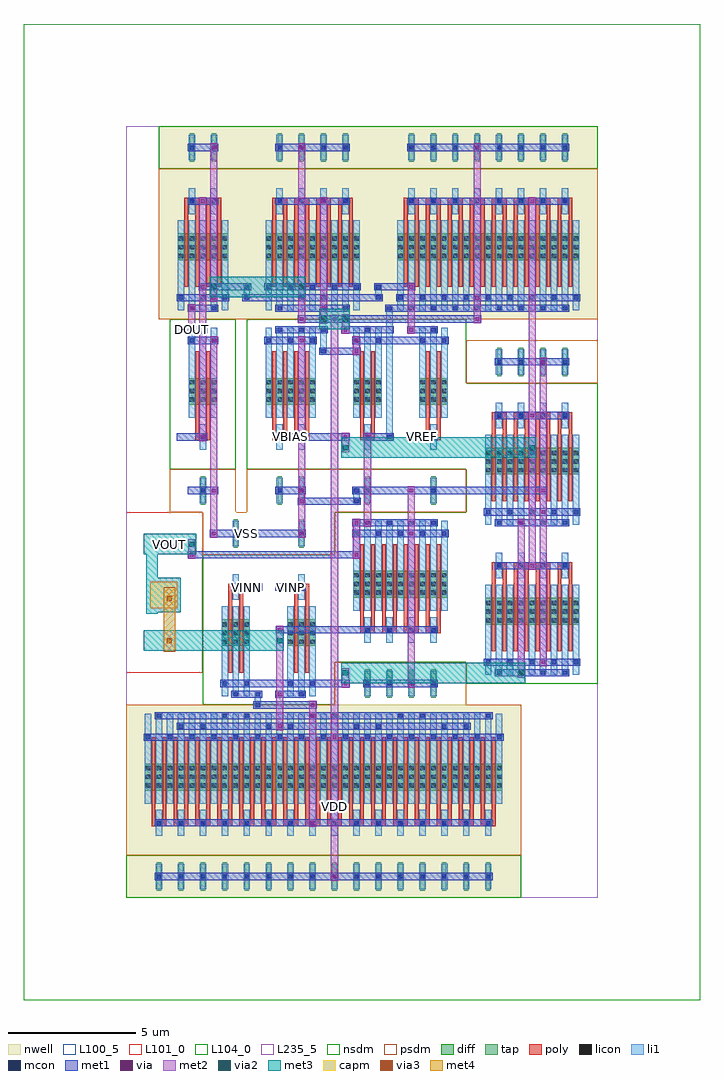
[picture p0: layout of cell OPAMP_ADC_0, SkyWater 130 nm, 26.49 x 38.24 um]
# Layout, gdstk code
from math import pi, radians
import gdstk
lib = gdstk.Library(unit=1e-6, precision=1e-09)
def R(c, l, rs):  # rectangles x0, y0, x1, y1
    for r in rs: c.add(gdstk.rectangle(r[:2], r[2:], *l))
def A(c, l, x, y, w, h, nx, ny, dx, dy):  # array of equal rectangles
    R(c, l, [(x+i*dx, y+j*dy, x+i*dx+w, y+j*dy+h) for i in range(nx) for j in range(ny)])
def P(c, l, *ps):  # polygons
    for p in ps: c.add(gdstk.Polygon(p, *l))
nwell = (64, 20)
diff = (65, 20)
tap = (65, 44)
poly = (66, 20)
licon = (66, 44)
li1 = (67, 20)
mcon = (67, 44)
met1 = (68, 20)
via = (68, 44)
met2 = (69, 20)
via2 = (69, 44)
met3 = (70, 20)
via3 = (70, 44)
met4 = (71, 20)
capm = (89, 44)
nsdm = (93, 44)
psdm = (94, 20)
L100_5 = (100, 5)
L101_0 = (101, 0)
L104_0 = (104, 0)
L235_5 = (235, 5)

scm_pmos_2270758_x8_y1_1 = lib.new_cell('SCM_PMOS_2270758_X8_Y1_1785374631')
R(scm_pmos_2270758_x8_y1_1, nwell, [(0,0,15.48,7.56)])
R(scm_pmos_2270758_x8_y1_1, diff, [(0.735,2.31,14.745,3.36)])
A(scm_pmos_2270758_x8_y1_1, tap, 1.205, 6.16, 0.17, 1.12, 16, 1, 0.86, 0)
A(scm_pmos_2270758_x8_y1_1, poly, 1, 1.26, 0.15, 3.36, 32, 1, 0.43, 0)
A(scm_pmos_2270758_x8_y1_1, poly, 1, 4.485, 0.58, 0.27, 16, 1, 0.86, 0)
A(scm_pmos_2270758_x8_y1_1, licon, 0.775, 2.39, 0.17, 0.17, 3, 3, 0.43, 0.34)
A(scm_pmos_2270758_x8_y1_1, licon, 1.635, 2.39, 0.17, 0.17, 3, 3, 0.43, 0.34)
A(scm_pmos_2270758_x8_y1_1, licon, 2.495, 2.39, 0.17, 0.17, 3, 3, 0.43, 0.34)
A(scm_pmos_2270758_x8_y1_1, licon, 3.355, 2.39, 0.17, 0.17, 3, 3, 0.43, 0.34)
A(scm_pmos_2270758_x8_y1_1, licon, 4.215, 2.39, 0.17, 0.17, 3, 3, 0.43, 0.34)
A(scm_pmos_2270758_x8_y1_1, licon, 5.075, 2.39, 0.17, 0.17, 3, 3, 0.43, 0.34)
A(scm_pmos_2270758_x8_y1_1, licon, 5.935, 2.39, 0.17, 0.17, 3, 3, 0.43, 0.34)
A(scm_pmos_2270758_x8_y1_1, licon, 6.795, 2.39, 0.17, 0.17, 3, 3, 0.43, 0.34)
A(scm_pmos_2270758_x8_y1_1, licon, 7.655, 2.39, 0.17, 0.17, 3, 3, 0.43, 0.34)
A(scm_pmos_2270758_x8_y1_1, licon, 8.515, 2.39, 0.17, 0.17, 3, 3, 0.43, 0.34)
A(scm_pmos_2270758_x8_y1_1, licon, 9.375, 2.39, 0.17, 0.17, 3, 3, 0.43, 0.34)
A(scm_pmos_2270758_x8_y1_1, licon, 10.235, 2.39, 0.17, 0.17, 3, 3, 0.43, 0.34)
A(scm_pmos_2270758_x8_y1_1, licon, 11.095, 2.39, 0.17, 0.17, 3, 3, 0.43, 0.34)
A(scm_pmos_2270758_x8_y1_1, licon, 11.955, 2.39, 0.17, 0.17, 3, 3, 0.43, 0.34)
A(scm_pmos_2270758_x8_y1_1, licon, 12.815, 2.39, 0.17, 0.17, 3, 3, 0.43, 0.34)
A(scm_pmos_2270758_x8_y1_1, licon, 13.675, 2.39, 0.17, 0.17, 3, 3, 0.43, 0.34)
A(scm_pmos_2270758_x8_y1_1, licon, 1.205, 4.535, 0.17, 0.17, 16, 2, 0.86, 2.1)
A(scm_pmos_2270758_x8_y1_1, li1, 0.735, 0.335, 0.25, 3.53, 33, 1, 0.43, 0)
A(scm_pmos_2270758_x8_y1_1, li1, 1.165, 4.115, 0.25, 1.01, 16, 2, 0.86, 2.1)
A(scm_pmos_2270758_x8_y1_1, mcon, 0.775, 1.175, 0.17, 0.17, 17, 1, 0.86, 0)
A(scm_pmos_2270758_x8_y1_1, mcon, 1.205, 4.535, 0.17, 0.17, 16, 2, 0.86, 2.1)
R(scm_pmos_2270758_x8_y1_1, mcon, [(1.205,0.335,1.375,0.505), (3.785,0.335,3.955,0.505), (4.645,0.335,4.815,0.505), (7.225,0.335,7.395,0.505), (8.085,0.335,8.255,0.505), (10.665,0.335,10.835,0.505), (11.525,0.335,11.695,0.505), (14.105,0.335,14.275,0.505), (2.065,0.755,2.235,0.925), (2.925,0.755,3.095,0.925), (5.505,0.755,5.675,0.925), (6.365,0.755,6.535,0.925), (8.945,0.755,9.115,0.925), (9.805,0.755,9.975,0.925), (12.385,0.755,12.555,0.925), (13.245,0.755,13.415,0.925)])
R(scm_pmos_2270758_x8_y1_1, met1, [(1.12,0.28,14.36,0.56), (1.98,0.7,13.5,0.98), (0.69,1.12,14.79,1.4), (1.12,4.48,14.36,4.76), (1.12,6.58,14.36,6.86)])
R(scm_pmos_2270758_x8_y1_1, via, [(7.235,0.345,7.385,0.495), (8.095,1.185,8.245,1.335), (7.235,4.545,7.385,4.695), (8.095,6.645,8.245,6.795)])
R(scm_pmos_2270758_x8_y1_1, met2, [(7.17,0.26,7.45,4.78), (8.03,1.1,8.31,6.88)])
R(scm_pmos_2270758_x8_y1_1, nsdm, [(0,5.88,15.48,7.56)])
R(scm_pmos_2270758_x8_y1_1, psdm, [(0,0,15.48,5.88)])
R(scm_pmos_2270758_x8_y1_1, L100_5, [(0,0,15.48,7.56)])

scm_pmos_89224135_x2_y1_ = lib.new_cell('SCM_PMOS_89224135_X2_Y1_1785374632')
R(scm_pmos_89224135_x2_y1_, nwell, [(0,0,5.16,7.56)])
R(scm_pmos_89224135_x2_y1_, diff, [(0.735,2.31,4.425,3.36)])
A(scm_pmos_89224135_x2_y1_, tap, 1.205, 6.16, 0.17, 1.12, 4, 1, 0.86, 0)
A(scm_pmos_89224135_x2_y1_, poly, 1, 1.26, 0.15, 3.36, 8, 1, 0.43, 0)
A(scm_pmos_89224135_x2_y1_, poly, 1, 4.485, 0.58, 0.27, 4, 1, 0.86, 0)
A(scm_pmos_89224135_x2_y1_, licon, 0.775, 2.39, 0.17, 0.17, 3, 3, 0.43, 0.34)
A(scm_pmos_89224135_x2_y1_, licon, 1.635, 2.39, 0.17, 0.17, 3, 3, 0.43, 0.34)
A(scm_pmos_89224135_x2_y1_, licon, 2.495, 2.39, 0.17, 0.17, 3, 3, 0.43, 0.34)
A(scm_pmos_89224135_x2_y1_, licon, 3.355, 2.39, 0.17, 0.17, 3, 3, 0.43, 0.34)
A(scm_pmos_89224135_x2_y1_, licon, 1.205, 4.535, 0.17, 0.17, 4, 2, 0.86, 2.1)
A(scm_pmos_89224135_x2_y1_, li1, 0.735, 0.335, 0.25, 3.53, 9, 1, 0.43, 0)
A(scm_pmos_89224135_x2_y1_, li1, 1.165, 4.115, 0.25, 1.01, 4, 2, 0.86, 2.1)
A(scm_pmos_89224135_x2_y1_, mcon, 0.775, 1.175, 0.17, 0.17, 5, 1, 0.86, 0)
A(scm_pmos_89224135_x2_y1_, mcon, 1.205, 4.535, 0.17, 0.17, 4, 2, 0.86, 2.1)
R(scm_pmos_89224135_x2_y1_, mcon, [(1.205,0.335,1.375,0.505), (3.785,0.335,3.955,0.505), (2.065,0.755,2.235,0.925), (2.925,0.755,3.095,0.925)])
R(scm_pmos_89224135_x2_y1_, met1, [(1.12,0.28,4.04,0.56), (1.98,0.7,3.18,0.98), (0.69,1.12,4.47,1.4), (1.12,4.48,4.04,4.76), (1.12,6.58,4.04,6.86)])
R(scm_pmos_89224135_x2_y1_, via, [(2.075,0.345,2.225,0.495), (2.935,1.185,3.085,1.335), (2.075,4.545,2.225,4.695), (2.935,6.645,3.085,6.795)])
R(scm_pmos_89224135_x2_y1_, met2, [(2.01,0.26,2.29,4.78), (2.87,1.1,3.15,6.88)])
R(scm_pmos_89224135_x2_y1_, nsdm, [(0,5.88,5.16,7.56)])
R(scm_pmos_89224135_x2_y1_, psdm, [(0,0,5.16,5.88)])
R(scm_pmos_89224135_x2_y1_, L100_5, [(0,0,5.16,7.56)])

nmos_s_66450264_x1_y1_17 = lib.new_cell('NMOS_S_66450264_X1_Y1_1785374624_1785374624')
R(nmos_s_66450264_x1_y1_17, diff, [(0.735,2.31,1.845,3.36)])
R(nmos_s_66450264_x1_y1_17, tap, [(1.205,6.16,1.375,7.28)])
R(nmos_s_66450264_x1_y1_17, poly, [(1,1.26,1.15,4.62), (1.43,1.26,1.58,4.62), (1,4.485,1.58,4.755)])
A(nmos_s_66450264_x1_y1_17, licon, 0.775, 2.39, 0.17, 0.17, 3, 3, 0.43, 0.34)
R(nmos_s_66450264_x1_y1_17, licon, [(1.205,4.535,1.375,4.705), (1.205,6.635,1.375,6.805)])
A(nmos_s_66450264_x1_y1_17, li1, 0.735, 0.335, 0.25, 3.53, 3, 1, 0.43, 0)
R(nmos_s_66450264_x1_y1_17, li1, [(1.165,4.115,1.415,5.125), (1.165,6.215,1.415,7.225)])
R(nmos_s_66450264_x1_y1_17, mcon, [(1.205,0.335,1.375,0.505), (0.775,0.755,0.945,0.925), (1.635,0.755,1.805,0.925), (1.205,4.535,1.375,4.705), (1.205,6.635,1.375,6.805)])
R(nmos_s_66450264_x1_y1_17, met1, [(0.26,0.28,1.46,0.56), (0.69,0.7,1.89,0.98), (0.26,4.48,1.46,4.76), (0.69,6.58,1.89,6.86)])
R(nmos_s_66450264_x1_y1_17, via, [(1.645,0.765,1.795,0.915), (1.645,6.645,1.795,6.795)])
R(nmos_s_66450264_x1_y1_17, met2, [(1.58,0.68,1.86,6.88)])
R(nmos_s_66450264_x1_y1_17, nsdm, [(0,0,2.58,5.88)])
R(nmos_s_66450264_x1_y1_17, psdm, [(0,5.88,2.58,7.56)])
R(nmos_s_66450264_x1_y1_17, L100_5, [(0,0,2.58,7.56)])

pmos_s_5293867_x2_y1_178 = lib.new_cell('PMOS_S_5293867_X2_Y1_1785374625_1785374624')
R(pmos_s_5293867_x2_y1_178, nwell, [(0,0,3.44,7.56)])
R(pmos_s_5293867_x2_y1_178, diff, [(0.735,2.31,2.705,3.36)])
R(pmos_s_5293867_x2_y1_178, tap, [(1.205,6.16,1.375,7.28), (2.065,6.16,2.235,7.28)])
A(pmos_s_5293867_x2_y1_178, poly, 1, 1.26, 0.15, 3.36, 4, 1, 0.43, 0)
R(pmos_s_5293867_x2_y1_178, poly, [(1,4.485,1.58,4.755), (1.86,4.485,2.44,4.755)])
A(pmos_s_5293867_x2_y1_178, licon, 0.775, 2.39, 0.17, 0.17, 3, 3, 0.43, 0.34)
A(pmos_s_5293867_x2_y1_178, licon, 1.635, 2.39, 0.17, 0.17, 3, 3, 0.43, 0.34)
R(pmos_s_5293867_x2_y1_178, licon, [(1.205,4.535,1.375,4.705), (2.065,4.535,2.235,4.705), (1.205,6.635,1.375,6.805), (2.065,6.635,2.235,6.805)])
A(pmos_s_5293867_x2_y1_178, li1, 0.735, 0.335, 0.25, 3.53, 5, 1, 0.43, 0)
R(pmos_s_5293867_x2_y1_178, li1, [(1.165,4.115,1.415,5.125), (2.025,4.115,2.275,5.125), (1.165,6.215,1.415,7.225), (2.025,6.215,2.275,7.225)])
A(pmos_s_5293867_x2_y1_178, mcon, 0.775, 0.755, 0.17, 0.17, 3, 1, 0.86, 0)
R(pmos_s_5293867_x2_y1_178, mcon, [(1.205,0.335,1.375,0.505), (2.065,0.335,2.235,0.505), (1.205,4.535,1.375,4.705), (2.065,4.535,2.235,4.705), (1.205,6.635,1.375,6.805), (2.065,6.635,2.235,6.805)])
R(pmos_s_5293867_x2_y1_178, met1, [(1.12,0.28,2.32,0.56), (0.69,0.7,2.75,0.98), (1.12,4.48,2.32,4.76), (1.12,6.58,2.32,6.86)])
R(pmos_s_5293867_x2_y1_178, via, [(2.075,0.765,2.225,0.915), (2.075,6.645,2.225,6.795)])
R(pmos_s_5293867_x2_y1_178, met2, [(2.01,0.68,2.29,6.88)])
R(pmos_s_5293867_x2_y1_178, nsdm, [(0,5.88,3.44,7.56)])
R(pmos_s_5293867_x2_y1_178, psdm, [(0,0,3.44,5.88)])
R(pmos_s_5293867_x2_y1_178, L100_5, [(0,0,3.44,7.56)])

inv_65002554_0_178537462 = lib.new_cell('INV_65002554_0_1785374624')
R(inv_65002554_0_178537462, met1, [(1.56,2.8,1.88,3.08), (1.56,2.8,1.88,3.08), (1.13,7,1.45,7.28), (1.13,7,1.45,7.28), (1.13,7.84,1.45,8.12), (1.13,7.84,1.45,8.12), (1.56,12.04,1.88,12.32), (1.56,12.04,1.88,12.32)])
P(inv_65002554_0_178537462, met1, [(0,0),(0,0),(0,0),(0,0)],
  [(0,0),(0,0),(0,0),(0,0)],
  [(0,0),(0,0),(0,0),(0,0)],
  [(0,0),(0,0),(0,0),(0,0)])
R(inv_65002554_0_178537462, via, [(1.645,2.865,1.795,3.015), (1.645,2.865,1.795,3.015), (1.215,7.065,1.365,7.215), (1.215,7.065,1.365,7.215), (1.215,7.905,1.365,8.055), (1.215,7.905,1.365,8.055), (1.645,12.105,1.795,12.255), (1.645,12.105,1.795,12.255)])
R(inv_65002554_0_178537462, met2, [(1.58,2.78,1.86,3.1), (1.58,2.78,1.86,3.1), (1.58,2.94,1.86,12.18), (1.15,6.98,1.43,7.3), (1.15,6.98,1.43,7.3), (1.15,7.14,1.43,7.98), (1.15,7.82,1.43,8.14), (1.15,7.82,1.43,8.14), (1.58,12.02,1.86,12.34), (1.58,12.02,1.86,12.34)])
P(inv_65002554_0_178537462, met2, [(0,0),(0,0),(0,0),(0,0)],
  [(0,0),(0,0),(0,0),(0,0)])
R(inv_65002554_0_178537462, L235_5, [(0,0,3.44,15.12)])
inv_65002554_0_178537462.add(gdstk.Reference(nmos_s_66450264_x1_y1_17, (0.43,7.56), x_reflection=True))
inv_65002554_0_178537462.add(gdstk.Reference(pmos_s_5293867_x2_y1_178, (0,7.56)))

cap_2t_96113034_17853746 = lib.new_cell('CAP_2T_96113034_1785374625')
R(cap_2t_96113034_17853746, met3, [(0.265,0.86,2.315,1.66), (1.76,2.32,2.21,4.84), (0.86,2.37,2.21,3.72), (0.265,4.64,2.315,5.44)])
R(cap_2t_96113034_17853746, via3, [(1.21,1.16,1.41,1.36), (1.21,2.82,1.41,3.02)])
R(cap_2t_96113034_17853746, met4, [(1.085,0.83,1.535,3.35)])
R(cap_2t_96113034_17853746, capm, [(1.01,2.52,2.06,3.57)])
R(cap_2t_96113034_17853746, L100_5, [(0,0,3.01,6.3)])
R(cap_2t_96113034_17853746, L101_0, [(0,0,3.01,6.3)])

nmos_s_72323505_x4_y2_17 = lib.new_cell('NMOS_S_72323505_X4_Y2_1785374628')
R(nmos_s_72323505_x4_y2_17, diff, [(0.735,2.31,4.425,3.36), (0.735,8.19,4.425,9.24)])
A(nmos_s_72323505_x4_y2_17, tap, 1.205, 12.04, 0.17, 1.12, 4, 1, 0.86, 0)
A(nmos_s_72323505_x4_y2_17, poly, 1, 1.26, 0.15, 3.36, 8, 2, 0.43, 5.88)
A(nmos_s_72323505_x4_y2_17, poly, 1, 4.485, 0.58, 0.27, 4, 2, 0.86, 5.88)
A(nmos_s_72323505_x4_y2_17, licon, 0.775, 2.39, 0.17, 0.17, 3, 3, 0.43, 0.34)
A(nmos_s_72323505_x4_y2_17, licon, 1.635, 2.39, 0.17, 0.17, 3, 3, 0.43, 0.34)
A(nmos_s_72323505_x4_y2_17, licon, 2.495, 2.39, 0.17, 0.17, 3, 3, 0.43, 0.34)
A(nmos_s_72323505_x4_y2_17, licon, 3.355, 2.39, 0.17, 0.17, 3, 3, 0.43, 0.34)
A(nmos_s_72323505_x4_y2_17, licon, 1.205, 4.535, 0.17, 0.17, 4, 2, 0.86, 5.88)
A(nmos_s_72323505_x4_y2_17, licon, 0.775, 8.27, 0.17, 0.17, 3, 3, 0.43, 0.34)
A(nmos_s_72323505_x4_y2_17, licon, 1.635, 8.27, 0.17, 0.17, 3, 3, 0.43, 0.34)
A(nmos_s_72323505_x4_y2_17, licon, 2.495, 8.27, 0.17, 0.17, 3, 3, 0.43, 0.34)
A(nmos_s_72323505_x4_y2_17, licon, 3.355, 8.27, 0.17, 0.17, 3, 3, 0.43, 0.34)
R(nmos_s_72323505_x4_y2_17, licon, [(1.205,12.515,1.375,12.685), (1.205,12.515,1.375,12.685), (2.065,12.515,2.235,12.685), (2.065,12.515,2.235,12.685), (2.925,12.515,3.095,12.685), (2.925,12.515,3.095,12.685), (3.785,12.515,3.955,12.685), (3.785,12.515,3.955,12.685)])
A(nmos_s_72323505_x4_y2_17, li1, 0.735, 0.335, 0.25, 3.53, 9, 2, 0.43, 5.88)
A(nmos_s_72323505_x4_y2_17, li1, 1.165, 4.115, 0.25, 1.01, 4, 2, 0.86, 5.88)
A(nmos_s_72323505_x4_y2_17, li1, 1.165, 12.095, 0.25, 1.01, 4, 1, 0.86, 0)
A(nmos_s_72323505_x4_y2_17, mcon, 1.205, 0.335, 0.17, 0.17, 4, 2, 0.86, 4.2)
A(nmos_s_72323505_x4_y2_17, mcon, 0.775, 0.755, 0.17, 0.17, 5, 2, 0.86, 5.88)
A(nmos_s_72323505_x4_y2_17, mcon, 1.205, 6.215, 0.17, 0.17, 4, 2, 0.86, 4.2)
A(nmos_s_72323505_x4_y2_17, mcon, 1.205, 12.515, 0.17, 0.17, 4, 1, 0.86, 0)
R(nmos_s_72323505_x4_y2_17, met1, [(1.12,0.28,4.04,0.56), (0.69,0.7,4.47,0.98), (1.12,4.48,4.04,4.76), (1.12,6.16,4.04,6.44), (0.69,6.58,4.47,6.86), (1.12,10.36,4.04,10.64), (1.12,12.46,4.04,12.74)])
A(nmos_s_72323505_x4_y2_17, via, 2.935, 0.765, 0.15, 0.15, 1, 3, 0, 5.88)
R(nmos_s_72323505_x4_y2_17, via, [(2.075,0.345,2.225,0.495), (2.505,4.545,2.655,4.695), (2.075,6.225,2.225,6.375), (2.505,10.425,2.655,10.575)])
R(nmos_s_72323505_x4_y2_17, met2, [(2.01,0.26,2.29,6.46), (2.87,0.68,3.15,12.76), (2.44,4.46,2.72,10.66)])
R(nmos_s_72323505_x4_y2_17, nsdm, [(0,0,5.16,11.76)])
R(nmos_s_72323505_x4_y2_17, psdm, [(0,11.76,5.16,13.44)])
R(nmos_s_72323505_x4_y2_17, L100_5, [(0,0,5.16,13.44)])

nmos_s_98719586_x4_y1_17 = lib.new_cell('NMOS_S_98719586_X4_Y1_1785374629')
R(nmos_s_98719586_x4_y1_17, diff, [(0.735,2.31,4.425,3.36)])
A(nmos_s_98719586_x4_y1_17, tap, 1.205, 6.16, 0.17, 1.12, 4, 1, 0.86, 0)
A(nmos_s_98719586_x4_y1_17, poly, 1, 1.26, 0.15, 3.36, 8, 1, 0.43, 0)
A(nmos_s_98719586_x4_y1_17, poly, 1, 4.485, 0.58, 0.27, 4, 1, 0.86, 0)
A(nmos_s_98719586_x4_y1_17, licon, 0.775, 2.39, 0.17, 0.17, 3, 3, 0.43, 0.34)
A(nmos_s_98719586_x4_y1_17, licon, 1.635, 2.39, 0.17, 0.17, 3, 3, 0.43, 0.34)
A(nmos_s_98719586_x4_y1_17, licon, 2.495, 2.39, 0.17, 0.17, 3, 3, 0.43, 0.34)
A(nmos_s_98719586_x4_y1_17, licon, 3.355, 2.39, 0.17, 0.17, 3, 3, 0.43, 0.34)
A(nmos_s_98719586_x4_y1_17, licon, 1.205, 4.535, 0.17, 0.17, 4, 2, 0.86, 2.1)
A(nmos_s_98719586_x4_y1_17, li1, 0.735, 0.335, 0.25, 3.53, 9, 1, 0.43, 0)
A(nmos_s_98719586_x4_y1_17, li1, 1.165, 4.115, 0.25, 1.01, 4, 2, 0.86, 2.1)
A(nmos_s_98719586_x4_y1_17, mcon, 1.205, 0.335, 0.17, 0.17, 4, 2, 0.86, 4.2)
A(nmos_s_98719586_x4_y1_17, mcon, 0.775, 0.755, 0.17, 0.17, 5, 1, 0.86, 0)
A(nmos_s_98719586_x4_y1_17, mcon, 1.205, 6.635, 0.17, 0.17, 4, 1, 0.86, 0)
R(nmos_s_98719586_x4_y1_17, met1, [(1.12,0.28,4.04,0.56), (0.69,0.7,4.47,0.98), (1.12,4.48,4.04,4.76), (1.12,6.58,4.04,6.86)])
R(nmos_s_98719586_x4_y1_17, via, [(2.935,0.765,3.085,0.915), (2.935,6.645,3.085,6.795)])
R(nmos_s_98719586_x4_y1_17, met2, [(2.87,0.68,3.15,6.88)])
R(nmos_s_98719586_x4_y1_17, nsdm, [(0,0,5.16,5.88)])
R(nmos_s_98719586_x4_y1_17, psdm, [(0,5.88,5.16,7.56)])
R(nmos_s_98719586_x4_y1_17, L100_5, [(0,0,5.16,7.56)])

nmos_s_67890029_x2_y1_17 = lib.new_cell('NMOS_S_67890029_X2_Y1_1785374627')
R(nmos_s_67890029_x2_y1_17, diff, [(0.735,2.31,2.705,3.36)])
R(nmos_s_67890029_x2_y1_17, tap, [(1.205,6.16,1.375,7.28), (2.065,6.16,2.235,7.28)])
A(nmos_s_67890029_x2_y1_17, poly, 1, 1.26, 0.15, 3.36, 4, 1, 0.43, 0)
R(nmos_s_67890029_x2_y1_17, poly, [(1,4.485,1.58,4.755), (1.86,4.485,2.44,4.755)])
A(nmos_s_67890029_x2_y1_17, licon, 0.775, 2.39, 0.17, 0.17, 3, 3, 0.43, 0.34)
A(nmos_s_67890029_x2_y1_17, licon, 1.635, 2.39, 0.17, 0.17, 3, 3, 0.43, 0.34)
R(nmos_s_67890029_x2_y1_17, licon, [(1.205,4.535,1.375,4.705), (2.065,4.535,2.235,4.705), (1.205,6.635,1.375,6.805), (2.065,6.635,2.235,6.805)])
A(nmos_s_67890029_x2_y1_17, li1, 0.735, 0.335, 0.25, 3.53, 5, 1, 0.43, 0)
R(nmos_s_67890029_x2_y1_17, li1, [(1.165,4.115,1.415,5.125), (2.025,4.115,2.275,5.125), (1.165,6.215,1.415,7.225), (2.025,6.215,2.275,7.225)])
A(nmos_s_67890029_x2_y1_17, mcon, 0.775, 0.755, 0.17, 0.17, 3, 1, 0.86, 0)
R(nmos_s_67890029_x2_y1_17, mcon, [(1.205,0.335,1.375,0.505), (2.065,0.335,2.235,0.505), (1.205,4.535,1.375,4.705), (2.065,4.535,2.235,4.705), (1.205,6.635,1.375,6.805), (2.065,6.635,2.235,6.805)])
R(nmos_s_67890029_x2_y1_17, met1, [(1.12,0.28,2.32,0.56), (0.69,0.7,2.75,0.98), (1.12,4.48,2.32,4.76), (1.12,6.58,2.32,6.86)])
R(nmos_s_67890029_x2_y1_17, via, [(2.075,0.765,2.225,0.915), (2.075,6.645,2.225,6.795)])
R(nmos_s_67890029_x2_y1_17, met2, [(2.01,0.68,2.29,6.88)])
R(nmos_s_67890029_x2_y1_17, nsdm, [(0,0,3.44,5.88)])
R(nmos_s_67890029_x2_y1_17, psdm, [(0,5.88,3.44,7.56)])
R(nmos_s_67890029_x2_y1_17, L100_5, [(0,0,3.44,7.56)])

pmos_s_62671986_x8_y1_17 = lib.new_cell('PMOS_S_62671986_X8_Y1_1785374630')
R(pmos_s_62671986_x8_y1_17, nwell, [(0,0,8.6,7.56)])
R(pmos_s_62671986_x8_y1_17, diff, [(0.735,2.31,7.865,3.36)])
A(pmos_s_62671986_x8_y1_17, tap, 1.205, 6.16, 0.17, 1.12, 8, 1, 0.86, 0)
A(pmos_s_62671986_x8_y1_17, poly, 1, 1.26, 0.15, 3.36, 16, 1, 0.43, 0)
A(pmos_s_62671986_x8_y1_17, poly, 1, 4.485, 0.58, 0.27, 8, 1, 0.86, 0)
A(pmos_s_62671986_x8_y1_17, licon, 0.775, 2.39, 0.17, 0.17, 3, 3, 0.43, 0.34)
A(pmos_s_62671986_x8_y1_17, licon, 1.635, 2.39, 0.17, 0.17, 3, 3, 0.43, 0.34)
A(pmos_s_62671986_x8_y1_17, licon, 2.495, 2.39, 0.17, 0.17, 3, 3, 0.43, 0.34)
A(pmos_s_62671986_x8_y1_17, licon, 3.355, 2.39, 0.17, 0.17, 3, 3, 0.43, 0.34)
A(pmos_s_62671986_x8_y1_17, licon, 4.215, 2.39, 0.17, 0.17, 3, 3, 0.43, 0.34)
A(pmos_s_62671986_x8_y1_17, licon, 5.075, 2.39, 0.17, 0.17, 3, 3, 0.43, 0.34)
A(pmos_s_62671986_x8_y1_17, licon, 5.935, 2.39, 0.17, 0.17, 3, 3, 0.43, 0.34)
A(pmos_s_62671986_x8_y1_17, licon, 6.795, 2.39, 0.17, 0.17, 3, 3, 0.43, 0.34)
A(pmos_s_62671986_x8_y1_17, licon, 1.205, 4.535, 0.17, 0.17, 8, 2, 0.86, 2.1)
A(pmos_s_62671986_x8_y1_17, li1, 0.735, 0.335, 0.25, 3.53, 17, 1, 0.43, 0)
A(pmos_s_62671986_x8_y1_17, li1, 1.165, 4.115, 0.25, 1.01, 8, 2, 0.86, 2.1)
A(pmos_s_62671986_x8_y1_17, mcon, 1.205, 0.335, 0.17, 0.17, 8, 2, 0.86, 4.2)
A(pmos_s_62671986_x8_y1_17, mcon, 0.775, 0.755, 0.17, 0.17, 9, 1, 0.86, 0)
A(pmos_s_62671986_x8_y1_17, mcon, 1.205, 6.635, 0.17, 0.17, 8, 1, 0.86, 0)
R(pmos_s_62671986_x8_y1_17, met1, [(1.12,0.28,7.48,0.56), (0.69,0.7,7.91,0.98), (1.12,4.48,7.48,4.76), (1.12,6.58,7.48,6.86)])
R(pmos_s_62671986_x8_y1_17, via, [(4.655,0.765,4.805,0.915), (4.655,6.645,4.805,6.795)])
R(pmos_s_62671986_x8_y1_17, met2, [(4.59,0.68,4.87,6.88)])
R(pmos_s_62671986_x8_y1_17, nsdm, [(0,5.88,8.6,7.56)])
R(pmos_s_62671986_x8_y1_17, psdm, [(0,0,8.6,5.88)])
R(pmos_s_62671986_x8_y1_17, L100_5, [(0,0,8.6,7.56)])

nmos_4t_95495835_x1_y1_1 = lib.new_cell('NMOS_4T_95495835_X1_Y1_1785374626')
R(nmos_4t_95495835_x1_y1_1, diff, [(0.735,2.31,1.845,3.36)])
R(nmos_4t_95495835_x1_y1_1, tap, [(1.205,6.16,1.375,7.28)])
R(nmos_4t_95495835_x1_y1_1, poly, [(1,1.26,1.15,4.62), (1.43,1.26,1.58,4.62), (1,4.485,1.58,4.755)])
A(nmos_4t_95495835_x1_y1_1, licon, 0.775, 2.39, 0.17, 0.17, 3, 3, 0.43, 0.34)
R(nmos_4t_95495835_x1_y1_1, licon, [(1.205,4.535,1.375,4.705), (1.205,6.635,1.375,6.805)])
A(nmos_4t_95495835_x1_y1_1, li1, 0.735, 0.335, 0.25, 3.53, 3, 1, 0.43, 0)
R(nmos_4t_95495835_x1_y1_1, li1, [(1.165,4.115,1.415,5.125), (1.165,6.215,1.415,7.225)])
R(nmos_4t_95495835_x1_y1_1, mcon, [(1.205,0.335,1.375,0.505), (0.775,0.755,0.945,0.925), (1.635,0.755,1.805,0.925), (1.205,4.535,1.375,4.705), (1.205,6.635,1.375,6.805)])
R(nmos_4t_95495835_x1_y1_1, met1, [(0.26,0.28,1.46,0.56), (0.69,0.7,1.89,0.98), (0.26,4.48,1.46,4.76), (0.26,6.58,1.46,6.86)])
R(nmos_4t_95495835_x1_y1_1, nsdm, [(0,0,2.58,5.88)])
R(nmos_4t_95495835_x1_y1_1, psdm, [(0,5.88,2.58,7.56)])
R(nmos_4t_95495835_x1_y1_1, L100_5, [(0,0,2.58,7.56)])

opamp_adc_0 = lib.new_cell('OPAMP_ADC_0')
R(opamp_adc_0, li1, [(5.035,7.475,5.285,7.645), (5.035,7.475,5.285,7.645), (5.035,7.56,5.285,7.98), (5.035,7.895,5.285,8.065), (5.035,7.895,5.285,8.065), (8.905,15.455,9.155,15.625), (8.905,15.455,9.155,15.625), (8.905,15.455,9.155,15.625), (8.905,15.455,9.155,15.625), (8.905,15.455,9.155,15.625), (8.905,15.455,9.155,15.625), (8.905,15.455,9.155,15.625), (8.905,15.455,9.155,15.625), (8.905,15.54,9.155,15.96), (8.905,15.875,9.155,16.045), (8.905,15.875,9.155,16.045), (8.905,15.875,9.155,16.045), (8.905,15.875,9.155,16.045), (8.905,15.875,9.155,16.045), (8.905,15.875,9.155,16.045), (8.905,15.875,9.155,16.045), (8.905,15.875,9.155,16.045), (10.195,17.975,10.445,18.145), (10.195,17.975,10.445,18.145), (10.195,18.06,10.445,23.1), (7.615,21.335,7.865,21.505), (7.615,21.335,7.865,21.505), (7.615,21.335,7.865,21.505), (7.615,21.335,7.865,21.505), (7.615,21.42,7.865,22.26), (7.615,22.175,7.865,22.345), (7.615,22.175,7.865,22.345), (7.615,22.175,7.865,22.345), (7.615,22.175,7.865,22.345), (10.195,23.015,10.445,23.185), (10.195,23.015,10.445,23.185), (4.605,23.435,4.855,23.605), (4.605,23.435,4.855,23.605), (4.605,23.435,4.855,23.605), (4.605,23.435,4.855,23.605), (9.765,23.435,10.015,23.605), (9.765,23.435,10.015,23.605), (4.605,23.52,4.855,23.94), (9.765,23.52,10.015,23.94), (4.605,23.855,4.855,24.025), (4.605,23.855,4.855,24.025), (4.605,23.855,4.855,24.025), (4.605,23.855,4.855,24.025), (9.765,23.855,10.015,24.025), (9.765,23.855,10.015,24.025)])
R(opamp_adc_0, mcon, [(5.075,7.475,5.245,7.645), (5.075,7.475,5.245,7.645), (5.075,7.895,5.245,8.065), (5.075,7.895,5.245,8.065), (8.945,15.455,9.115,15.625), (8.945,15.455,9.115,15.625), (8.945,15.455,9.115,15.625), (8.945,15.455,9.115,15.625), (8.945,15.455,9.115,15.625), (8.945,15.455,9.115,15.625), (8.945,15.455,9.115,15.625), (8.945,15.455,9.115,15.625), (8.945,15.875,9.115,16.045), (8.945,15.875,9.115,16.045), (8.945,15.875,9.115,16.045), (8.945,15.875,9.115,16.045), (8.945,15.875,9.115,16.045), (8.945,15.875,9.115,16.045), (8.945,15.875,9.115,16.045), (8.945,15.875,9.115,16.045), (10.235,17.975,10.405,18.145), (10.235,17.975,10.405,18.145), (7.655,21.335,7.825,21.505), (7.655,21.335,7.825,21.505), (7.655,21.335,7.825,21.505), (7.655,21.335,7.825,21.505), (7.655,22.175,7.825,22.345), (7.655,22.175,7.825,22.345), (7.655,22.175,7.825,22.345), (7.655,22.175,7.825,22.345), (10.235,23.015,10.405,23.185), (10.235,23.015,10.405,23.185), (4.645,23.435,4.815,23.605), (4.645,23.435,4.815,23.605), (4.645,23.435,4.815,23.605), (4.645,23.435,4.815,23.605), (9.805,23.435,9.975,23.605), (9.805,23.435,9.975,23.605), (4.645,23.855,4.815,24.025), (4.645,23.855,4.815,24.025), (4.645,23.855,4.815,24.025), (4.645,23.855,4.815,24.025), (9.805,23.855,9.975,24.025), (9.805,23.855,9.975,24.025)])
R(opamp_adc_0, met1, [(5.86,6.58,6.18,6.86), (5.86,6.58,6.18,6.86), (5.86,6.58,6.18,6.86), (5.86,6.58,6.18,6.86), (4.99,7.42,5.33,7.7), (4.99,7.42,5.33,7.7), (5.16,7.42,7.31,7.7), (7.15,7.42,7.47,7.7), (7.15,7.42,7.47,7.7), (4.99,7.84,5.33,8.12), (4.99,7.84,5.33,8.12), (5.86,7.84,6.18,8.12), (5.86,7.84,6.18,8.12), (5.86,7.84,6.18,8.12), (5.86,7.84,6.18,8.12), (5.86,7.84,6.18,8.12), (5.86,7.84,6.18,8.12), (4.73,8.26,6.45,8.54), (7.31,8.26,8.6,8.54), (8.44,8.26,8.76,8.54), (8.44,8.26,8.76,8.54), (5.86,10.36,6.18,10.64), (5.86,10.36,6.18,10.64), (6.02,10.36,9.46,10.64), (2.42,13.3,2.74,13.58), (2.42,13.3,2.74,13.58), (2.42,13.3,2.74,13.58), (2.42,13.3,2.74,13.58), (2.42,13.3,2.74,13.58), (2.42,13.3,2.74,13.58), (2.58,13.3,9.03,13.58), (8.87,13.3,9.19,13.58), (8.87,13.3,9.19,13.58), (8.87,13.3,9.19,13.58), (8.87,13.3,9.19,13.58), (8.87,13.3,9.19,13.58), (8.87,13.3,9.19,13.58), (3.28,14.14,3.6,14.42), (3.28,14.14,3.6,14.42), (3.28,14.14,3.6,14.42), (3.28,14.14,3.6,14.42), (3.28,14.14,3.6,14.42), (3.28,14.14,3.6,14.42), (3.28,14.14,3.6,14.42), (3.28,14.14,3.6,14.42), (3.28,14.14,3.6,14.42), (3.28,14.14,3.6,14.42), (3.44,14.14,4.3,14.42), (5.16,14.14,6.02,14.42), (6.72,14.14,7.04,14.42), (6.72,14.14,7.04,14.42), (6.72,14.14,7.04,14.42), (6.72,14.14,7.04,14.42), (6.72,14.14,7.04,14.42), (6.72,14.14,7.04,14.42), (6.72,14.14,7.04,14.42), (6.72,14.14,7.04,14.42), (6.72,14.14,7.04,14.42), (6.72,14.14,7.04,14.42), (6.72,14.14,7.04,14.42), (6.72,14.14,7.04,14.42), (8.87,14.56,9.19,14.84), (8.87,14.56,9.19,14.84), (8.87,14.56,9.19,14.84), (8.87,14.56,9.19,14.84), (8.87,14.56,9.19,14.84), (8.87,14.56,9.19,14.84), (9.03,14.56,9.46,14.84), (9.3,14.56,9.62,14.84), (9.3,14.56,9.62,14.84), (9.3,14.56,9.62,14.84), (9.3,14.56,9.62,14.84), (6.72,15.4,7.04,15.68), (6.72,15.4,7.04,15.68), (6.72,15.4,7.04,15.68), (6.72,15.4,7.04,15.68), (6.72,15.4,7.04,15.68), (6.72,15.4,7.04,15.68), (6.72,15.4,7.04,15.68), (6.72,15.4,7.04,15.68), (6.88,15.4,9.03,15.68), (8.86,15.4,9.2,15.68), (8.86,15.4,9.2,15.68), (8.86,15.4,9.2,15.68), (8.86,15.4,9.2,15.68), (8.86,15.4,9.2,15.68), (8.86,15.4,9.2,15.68), (8.86,15.4,9.2,15.68), (8.86,15.4,9.2,15.68), (8.86,15.82,9.2,16.1), (8.86,15.82,9.2,16.1), (8.86,15.82,9.2,16.1), (8.86,15.82,9.2,16.1), (8.86,15.82,9.2,16.1), (8.86,15.82,9.2,16.1), (8.86,15.82,9.2,16.1), (8.86,15.82,9.2,16.1), (9.03,15.82,9.46,16.1), (10.32,15.82,11.18,16.1), (11.02,15.82,11.34,16.1), (11.02,15.82,11.34,16.1), (11.02,15.82,11.34,16.1), (11.02,15.82,11.34,16.1), (12.04,15.82,16.34,16.1), (16.18,15.82,16.5,16.1), (16.18,15.82,16.5,16.1), (6.88,17.92,8.6,18.2), (8.44,17.92,8.76,18.2), (8.44,17.92,8.76,18.2), (8.44,17.92,8.76,18.2), (8.44,17.92,8.76,18.2), (9.3,17.92,9.62,18.2), (9.3,17.92,9.62,18.2), (9.3,17.92,9.62,18.2), (9.3,17.92,9.62,18.2), (10.15,17.92,10.49,18.2), (10.15,17.92,10.49,18.2), (7.57,21.28,7.91,21.56), (7.57,21.28,7.91,21.56), (7.57,21.28,7.91,21.56), (7.57,21.28,7.91,21.56), (7.74,21.28,9.03,21.56), (8.87,21.28,9.19,21.56), (8.87,21.28,9.19,21.56), (8.87,21.28,9.19,21.56), (8.87,21.28,9.19,21.56), (8.87,21.7,9.19,21.98), (8.87,21.7,9.19,21.98), (8.87,21.7,9.19,21.98), (8.87,21.7,9.19,21.98), (9.89,21.7,11.61,21.98), (6.88,22.12,7.74,22.4), (7.57,22.12,7.91,22.4), (7.57,22.12,7.91,22.4), (7.57,22.12,7.91,22.4), (7.57,22.12,7.91,22.4), (8.44,22.12,8.76,22.4), (8.44,22.12,8.76,22.4), (8.6,22.12,9.46,22.4), (11.02,22.12,11.34,22.4), (11.02,22.12,11.34,22.4), (6.72,22.54,7.04,22.82), (6.72,22.54,7.04,22.82), (6.72,22.54,7.04,22.82), (6.72,22.54,7.04,22.82), (6.72,22.54,7.04,22.82), (6.72,22.54,7.04,22.82), (6.88,22.54,8.17,22.82), (8.01,22.54,8.33,22.82), (8.01,22.54,8.33,22.82), (8.01,22.54,8.33,22.82), (8.01,22.54,8.33,22.82), (8.01,22.54,8.33,22.82), (8.01,22.54,8.33,22.82), (8.17,22.54,13.76,22.82), (13.6,22.54,13.92,22.82), (13.6,22.54,13.92,22.82), (10.15,22.96,10.49,23.24), (10.15,22.96,10.49,23.24), (10.32,22.96,11.18,23.24), (4.56,23.38,4.9,23.66), (4.56,23.38,4.9,23.66), (4.56,23.38,4.9,23.66), (4.56,23.38,4.9,23.66), (4.73,23.38,6.88,23.66), (7.74,23.38,9.89,23.66), (9.72,23.38,10.06,23.66), (9.72,23.38,10.06,23.66), (2.85,23.8,3.17,24.08), (2.85,23.8,3.17,24.08), (2.85,23.8,3.17,24.08), (2.85,23.8,3.17,24.08), (3.01,23.8,4.73,24.08), (4.56,23.8,4.9,24.08), (4.56,23.8,4.9,24.08), (4.56,23.8,4.9,24.08), (4.56,23.8,4.9,24.08), (9.72,23.8,10.06,24.08), (9.72,23.8,10.06,24.08), (9.89,23.8,11.18,24.08), (11.02,23.8,11.34,24.08), (11.02,23.8,11.34,24.08), (15.75,27.16,16.07,27.44), (15.75,27.16,16.07,27.44)])
P(opamp_adc_0, met1, [(0,0),(0,0),(0,0),(0,0)],
  [(0,0),(0,0),(0,0),(0,0)],
  [(0,0),(0,0),(0,0),(0,0)],
  [(0,0),(0,0),(0,0),(0,0)],
  [(0,0),(0,0),(0,0),(0,0)],
  [(0,0),(0,0),(0,0),(0,0)],
  [(0,0),(0,0),(0,0),(0,0)],
  [(0,0),(0,0),(0,0),(0,0)],
  [(0,0),(0,0),(0,0),(0,0)],
  [(0,0),(0,0),(0,0),(0,0)],
  [(0,0),(0,0),(0,0),(0,0)],
  [(0,0),(0,0),(0,0),(0,0)],
  [(0,0),(0,0),(0,0),(0,0)],
  [(0,0),(0,0),(0,0),(0,0)],
  [(0,0),(0,0),(0,0),(0,0)],
  [(0,0),(0,0),(0,0),(0,0)],
  [(0,0),(0,0),(0,0),(0,0)],
  [(0,0),(0,0),(0,0),(0,0)],
  [(0,0),(0,0),(0,0),(0,0)],
  [(0,0),(0,0),(0,0),(0,0)],
  [(0,0),(0,0),(0,0),(0,0)],
  [(0,0),(0,0),(0,0),(0,0)],
  [(0,0),(0,0),(0,0),(0,0)],
  [(0,0),(0,0),(0,0),(0,0)],
  [(0,0),(0,0),(0,0),(0,0)],
  [(0,0),(0,0),(0,0),(0,0)],
  [(0,0),(0,0),(0,0),(0,0)],
  [(0,0),(0,0),(0,0),(0,0)],
  [(0,0),(0,0),(0,0),(0,0)],
  [(0,0),(0,0),(0,0),(0,0)],
  [(0,0),(0,0),(0,0),(0,0)],
  [(0,0),(0,0),(0,0),(0,0)],
  [(0,0),(0,0),(0,0),(0,0)],
  [(0,0),(0,0),(0,0),(0,0)],
  [(0,0),(0,0),(0,0),(0,0)],
  [(0,0),(0,0),(0,0),(0,0)],
  [(0,0),(0,0),(0,0),(0,0)],
  [(0,0),(0,0),(0,0),(0,0)])
R(opamp_adc_0, via, [(5.945,6.645,6.095,6.795), (5.945,6.645,6.095,6.795), (5.945,6.645,6.095,6.795), (5.945,6.645,6.095,6.795), (7.235,7.485,7.385,7.635), (7.235,7.485,7.385,7.635), (5.945,7.905,6.095,8.055), (5.945,7.905,6.095,8.055), (5.945,7.905,6.095,8.055), (5.945,7.905,6.095,8.055), (5.945,7.905,6.095,8.055), (5.945,7.905,6.095,8.055), (8.525,8.325,8.675,8.475), (8.525,8.325,8.675,8.475), (5.945,10.425,6.095,10.575), (5.945,10.425,6.095,10.575), (2.505,13.365,2.655,13.515), (2.505,13.365,2.655,13.515), (2.505,13.365,2.655,13.515), (2.505,13.365,2.655,13.515), (2.505,13.365,2.655,13.515), (2.505,13.365,2.655,13.515), (8.955,13.365,9.105,13.515), (8.955,13.365,9.105,13.515), (8.955,13.365,9.105,13.515), (8.955,13.365,9.105,13.515), (8.955,13.365,9.105,13.515), (8.955,13.365,9.105,13.515), (3.365,14.205,3.515,14.355), (3.365,14.205,3.515,14.355), (3.365,14.205,3.515,14.355), (3.365,14.205,3.515,14.355), (3.365,14.205,3.515,14.355), (3.365,14.205,3.515,14.355), (3.365,14.205,3.515,14.355), (3.365,14.205,3.515,14.355), (3.365,14.205,3.515,14.355), (3.365,14.205,3.515,14.355), (6.805,14.205,6.955,14.355), (6.805,14.205,6.955,14.355), (6.805,14.205,6.955,14.355), (6.805,14.205,6.955,14.355), (6.805,14.205,6.955,14.355), (6.805,14.205,6.955,14.355), (6.805,14.205,6.955,14.355), (6.805,14.205,6.955,14.355), (6.805,14.205,6.955,14.355), (6.805,14.205,6.955,14.355), (6.805,14.205,6.955,14.355), (6.805,14.205,6.955,14.355), (8.955,14.625,9.105,14.775), (8.955,14.625,9.105,14.775), (8.955,14.625,9.105,14.775), (8.955,14.625,9.105,14.775), (8.955,14.625,9.105,14.775), (8.955,14.625,9.105,14.775), (9.385,14.625,9.535,14.775), (9.385,14.625,9.535,14.775), (9.385,14.625,9.535,14.775), (9.385,14.625,9.535,14.775), (6.805,15.465,6.955,15.615), (6.805,15.465,6.955,15.615), (6.805,15.465,6.955,15.615), (6.805,15.465,6.955,15.615), (6.805,15.465,6.955,15.615), (6.805,15.465,6.955,15.615), (6.805,15.465,6.955,15.615), (6.805,15.465,6.955,15.615), (11.105,15.885,11.255,16.035), (11.105,15.885,11.255,16.035), (11.105,15.885,11.255,16.035), (11.105,15.885,11.255,16.035), (16.265,15.885,16.415,16.035), (16.265,15.885,16.415,16.035), (8.525,17.985,8.675,18.135), (8.525,17.985,8.675,18.135), (8.525,17.985,8.675,18.135), (8.525,17.985,8.675,18.135), (9.385,17.985,9.535,18.135), (9.385,17.985,9.535,18.135), (9.385,17.985,9.535,18.135), (9.385,17.985,9.535,18.135), (8.955,21.345,9.105,21.495), (8.955,21.345,9.105,21.495), (8.955,21.345,9.105,21.495), (8.955,21.345,9.105,21.495), (8.955,21.765,9.105,21.915), (8.955,21.765,9.105,21.915), (8.955,21.765,9.105,21.915), (8.955,21.765,9.105,21.915), (8.525,22.185,8.675,22.335), (8.525,22.185,8.675,22.335), (11.105,22.185,11.255,22.335), (11.105,22.185,11.255,22.335), (6.805,22.605,6.955,22.755), (6.805,22.605,6.955,22.755), (6.805,22.605,6.955,22.755), (6.805,22.605,6.955,22.755), (6.805,22.605,6.955,22.755), (6.805,22.605,6.955,22.755), (8.095,22.605,8.245,22.755), (8.095,22.605,8.245,22.755), (8.095,22.605,8.245,22.755), (8.095,22.605,8.245,22.755), (8.095,22.605,8.245,22.755), (8.095,22.605,8.245,22.755), (13.685,22.605,13.835,22.755), (13.685,22.605,13.835,22.755), (2.935,23.865,3.085,24.015), (2.935,23.865,3.085,24.015), (2.935,23.865,3.085,24.015), (2.935,23.865,3.085,24.015), (11.105,23.865,11.255,24.015), (11.105,23.865,11.255,24.015), (15.835,27.225,15.985,27.375), (15.835,27.225,15.985,27.375)])
R(opamp_adc_0, met2, [(8.03,6.3,8.31,22.68), (5.88,6.56,6.16,6.88), (5.88,6.56,6.16,6.88), (5.88,6.56,6.16,6.88), (5.88,6.56,6.16,6.88), (5.88,6.72,6.16,7.98), (7.17,7.14,7.45,7.56), (7.17,7.4,7.45,7.72), (7.17,7.4,7.45,7.72), (5.88,7.82,6.16,8.14), (5.88,7.82,6.16,8.14), (5.88,7.82,6.16,8.14), (5.88,7.82,6.16,8.14), (5.88,7.82,6.16,8.14), (5.88,7.82,6.16,8.14), (5.88,7.98,6.16,10.08), (8.46,8.24,8.74,8.56), (8.46,8.24,8.74,8.56), (8.46,8.4,8.74,8.82), (8.46,8.635,8.74,9.005), (8.46,8.635,8.74,9.005), (15.34,8.635,15.62,9.005), (15.34,8.635,15.62,9.005), (5.88,9.895,6.16,10.265), (5.88,9.895,6.16,10.265), (5.88,9.895,6.16,10.265), (5.88,9.895,6.16,10.265), (5.88,9.895,6.16,10.265), (5.88,9.895,6.16,10.265), (5.88,10.08,6.16,10.5), (5.88,10.34,6.16,10.66), (5.88,10.34,6.16,10.66), (2.44,13.28,2.72,13.6), (2.44,13.28,2.72,13.6), (2.44,13.28,2.72,13.6), (2.44,13.28,2.72,13.6), (2.44,13.28,2.72,13.6), (2.44,13.28,2.72,13.6), (8.89,13.28,9.17,13.6), (8.89,13.28,9.17,13.6), (8.89,13.28,9.17,13.6), (8.89,13.28,9.17,13.6), (8.89,13.28,9.17,13.6), (8.89,13.28,9.17,13.6), (2.44,13.44,2.72,13.86), (8.89,13.44,9.17,14.7), (2.44,13.675,2.72,14.045), (2.44,13.675,2.72,14.045), (2.44,13.675,2.72,14.045), (2.44,13.675,2.72,14.045), (2.44,13.675,2.72,14.045), (2.44,13.675,2.72,14.045), (3.3,14.12,3.58,14.44), (3.3,14.12,3.58,14.44), (3.3,14.12,3.58,14.44), (3.3,14.12,3.58,14.44), (3.3,14.12,3.58,14.44), (3.3,14.12,3.58,14.44), (3.3,14.12,3.58,14.44), (3.3,14.12,3.58,14.44), (3.3,14.12,3.58,14.44), (3.3,14.12,3.58,14.44), (6.74,14.12,7.02,14.44), (6.74,14.12,7.02,14.44), (6.74,14.12,7.02,14.44), (6.74,14.12,7.02,14.44), (6.74,14.12,7.02,14.44), (6.74,14.12,7.02,14.44), (6.74,14.12,7.02,14.44), (6.74,14.12,7.02,14.44), (6.74,14.12,7.02,14.44), (6.74,14.12,7.02,14.44), (6.74,14.12,7.02,14.44), (6.74,14.12,7.02,14.44), (3.3,14.28,3.58,15.96), (6.74,14.28,7.02,15.96), (11.04,14.28,11.32,15.96), (8.89,14.54,9.17,14.86), (8.89,14.54,9.17,14.86), (8.89,14.54,9.17,14.86), (8.89,14.54,9.17,14.86), (8.89,14.54,9.17,14.86), (8.89,14.54,9.17,14.86), (9.32,14.54,9.6,14.86), (9.32,14.54,9.6,14.86), (9.32,14.54,9.6,14.86), (9.32,14.54,9.6,14.86), (9.32,14.7,9.6,18.06), (6.74,15.38,7.02,15.7), (6.74,15.38,7.02,15.7), (6.74,15.38,7.02,15.7), (6.74,15.38,7.02,15.7), (6.74,15.38,7.02,15.7), (6.74,15.38,7.02,15.7), (6.74,15.38,7.02,15.7), (6.74,15.38,7.02,15.7), (11.04,15.8,11.32,16.12), (11.04,15.8,11.32,16.12), (11.04,15.8,11.32,16.12), (11.04,15.8,11.32,16.12), (16.2,15.8,16.48,16.12), (16.2,15.8,16.48,16.12), (8.46,17.455,8.74,17.825), (8.46,17.455,8.74,17.825), (8.46,17.455,8.74,17.825), (8.46,17.455,8.74,17.825), (15.77,17.455,16.05,17.825), (15.77,17.455,16.05,17.825), (15.77,17.455,16.05,17.825), (15.77,17.455,16.05,17.825), (8.46,17.64,8.74,18.06), (8.46,17.9,8.74,18.22), (8.46,17.9,8.74,18.22), (8.46,17.9,8.74,18.22), (8.46,17.9,8.74,18.22), (9.32,17.9,9.6,18.22), (9.32,17.9,9.6,18.22), (9.32,17.9,9.6,18.22), (9.32,17.9,9.6,18.22), (15.77,18.9,16.05,27.3), (8.89,21.26,9.17,21.58), (8.89,21.26,9.17,21.58), (8.89,21.26,9.17,21.58), (8.89,21.26,9.17,21.58), (8.89,21.42,9.17,21.84), (8.89,21.68,9.17,22), (8.89,21.68,9.17,22), (8.89,21.68,9.17,22), (8.89,21.68,9.17,22), (8.46,22.1,8.74,22.42), (8.46,22.1,8.74,22.42), (11.04,22.1,11.32,22.42), (11.04,22.1,11.32,22.42), (8.46,22.26,8.74,22.68), (11.04,22.26,11.32,23.94), (7.6,22.495,7.88,22.865), (7.6,22.495,7.88,22.865), (8.46,22.495,8.74,22.865), (8.46,22.495,8.74,22.865), (6.74,22.52,7.02,22.84), (6.74,22.52,7.02,22.84), (6.74,22.52,7.02,22.84), (6.74,22.52,7.02,22.84), (6.74,22.52,7.02,22.84), (6.74,22.52,7.02,22.84), (8.03,22.52,8.31,22.84), (8.03,22.52,8.31,22.84), (8.03,22.52,8.31,22.84), (8.03,22.52,8.31,22.84), (8.03,22.52,8.31,22.84), (8.03,22.52,8.31,22.84), (13.62,22.52,13.9,22.84), (13.62,22.52,13.9,22.84), (6.74,22.68,7.02,23.94), (7.6,22.68,7.88,23.1), (13.62,22.68,13.9,23.52), (3.3,23.755,3.58,24.125), (3.3,23.755,3.58,24.125), (3.3,23.755,3.58,24.125), (3.3,23.755,3.58,24.125), (6.74,23.755,7.02,24.125), (6.74,23.755,7.02,24.125), (6.74,23.755,7.02,24.125), (6.74,23.755,7.02,24.125), (2.87,23.78,3.15,24.1), (2.87,23.78,3.15,24.1), (2.87,23.78,3.15,24.1), (2.87,23.78,3.15,24.1), (11.04,23.78,11.32,24.1), (11.04,23.78,11.32,24.1), (15.77,27.14,16.05,27.46), (15.77,27.14,16.05,27.46)])
P(opamp_adc_0, met2, [(0,0),(0,0),(0,0),(0,0)],
  [(0,0),(0,0),(0,0),(0,0)],
  [(0,0),(0,0),(0,0),(0,0)],
  [(0,0),(0,0),(0,0),(0,0)],
  [(0,0),(0,0),(0,0),(0,0)],
  [(0,0),(0,0),(0,0),(0,0)],
  [(0,0),(0,0),(0,0),(0,0)],
  [(0,0),(0,0),(0,0),(0,0)],
  [(0,0),(0,0),(0,0),(0,0)],
  [(0,0),(0,0),(0,0),(0,0)],
  [(0,0),(0,0),(0,0),(0,0)],
  [(0,0),(0,0),(0,0),(0,0)],
  [(0,0),(0,0),(0,0),(0,0)],
  [(0,0),(0,0),(0,0),(0,0)],
  [(0,0),(0,0),(0,0),(0,0)])
R(opamp_adc_0, via2, [(8.5,8.72,8.7,8.92), (8.5,8.72,8.7,8.92), (15.38,8.72,15.58,8.92), (15.38,8.72,15.58,8.92), (5.92,9.98,6.12,10.18), (5.92,9.98,6.12,10.18), (5.92,9.98,6.12,10.18), (5.92,9.98,6.12,10.18), (5.92,9.98,6.12,10.18), (5.92,9.98,6.12,10.18), (2.48,13.76,2.68,13.96), (2.48,13.76,2.68,13.96), (2.48,13.76,2.68,13.96), (2.48,13.76,2.68,13.96), (2.48,13.76,2.68,13.96), (2.48,13.76,2.68,13.96), (8.5,17.54,8.7,17.74), (8.5,17.54,8.7,17.74), (8.5,17.54,8.7,17.74), (8.5,17.54,8.7,17.74), (15.81,17.54,16.01,17.74), (15.81,17.54,16.01,17.74), (15.81,17.54,16.01,17.74), (15.81,17.54,16.01,17.74), (7.64,22.58,7.84,22.78), (7.64,22.58,7.84,22.78), (8.5,22.58,8.7,22.78), (8.5,22.58,8.7,22.78), (3.34,23.84,3.54,24.04), (3.34,23.84,3.54,24.04), (3.34,23.84,3.54,24.04), (3.34,23.84,3.54,24.04), (6.78,23.84,6.98,24.04), (6.78,23.84,6.98,24.04), (6.78,23.84,6.98,24.04), (6.78,23.84,6.98,24.04)])
R(opamp_adc_0, met3, [(8.435,8.42,8.765,9.22), (8.435,8.42,8.765,9.22), (8.6,8.42,15.48,9.22), (15.315,8.42,15.645,9.22), (15.315,8.42,15.645,9.22), (2.58,9.68,6.02,10.48), (5.855,9.68,6.185,10.48), (5.855,9.68,6.185,10.48), (5.855,9.68,6.185,10.48), (5.855,9.68,6.185,10.48), (5.855,9.68,6.185,10.48), (5.855,9.68,6.185,10.48), (2.415,13.46,2.745,14.26), (2.415,13.46,2.745,14.26), (2.415,13.46,2.745,14.26), (2.415,13.46,2.745,14.26), (2.415,13.46,2.745,14.26), (2.415,13.46,2.745,14.26), (8.435,17.24,8.765,18.04), (8.435,17.24,8.765,18.04), (8.435,17.24,8.765,18.04), (8.435,17.24,8.765,18.04), (8.6,17.24,15.91,18.04), (15.745,17.24,16.075,18.04), (15.745,17.24,16.075,18.04), (15.745,17.24,16.075,18.04), (15.745,17.24,16.075,18.04), (7.575,22.28,7.905,23.08), (7.575,22.28,7.905,23.08), (7.74,22.28,8.6,23.08), (8.435,22.28,8.765,23.08), (8.435,22.28,8.765,23.08), (3.275,23.54,3.605,24.34), (3.275,23.54,3.605,24.34), (3.275,23.54,3.605,24.34), (3.275,23.54,3.605,24.34), (3.44,23.54,6.88,24.34), (6.715,23.54,7.045,24.34), (6.715,23.54,7.045,24.34), (6.715,23.54,7.045,24.34), (6.715,23.54,7.045,24.34)])
P(opamp_adc_0, met3, [(0,0),(0,0),(0,0),(0,0)],
  [(0,0),(0,0),(0,0),(0,0)],
  [(0,0),(0,0),(0,0),(0,0)])
R(opamp_adc_0, L104_0, [(-4,-4,22.49,34.24)])
R(opamp_adc_0, L235_5, [(0,0,18.49,30.24)])
opamp_adc_0.add(gdstk.Reference(scm_pmos_2270758_x8_y1_1, (0,7.56), x_reflection=True))
opamp_adc_0.add(gdstk.Reference(scm_pmos_89224135_x2_y1_, (9.89,22.68), rotation=pi, x_reflection=True))
opamp_adc_0.add(gdstk.Reference(inv_65002554_0_178537462, (1.29,15.12)))
opamp_adc_0.add(gdstk.Reference(cap_2t_96113034_17853746, (3.01,8.82), rotation=pi, x_reflection=True))
opamp_adc_0.add(gdstk.Reference(nmos_s_72323505_x4_y2_17, (13.33,8.4)))
opamp_adc_0.add(gdstk.Reference(nmos_s_98719586_x4_y1_17, (8.17,15.12), x_reflection=True))
opamp_adc_0.add(gdstk.Reference(nmos_s_67890029_x2_y1_17, (4.73,22.68), x_reflection=True))
opamp_adc_0.add(gdstk.Reference(pmos_s_62671986_x8_y1_17, (18.49,22.68), rotation=pi, x_reflection=True))
opamp_adc_0.add(gdstk.Reference(nmos_4t_95495835_x1_y1_1, (5.59,7.56), rotation=pi, x_reflection=True))
opamp_adc_0.add(gdstk.Reference(nmos_4t_95495835_x1_y1_1, (5.59,7.56)))
opamp_adc_0.add(gdstk.Reference(nmos_4t_95495835_x1_y1_1, (10.75,22.68), rotation=pi))
opamp_adc_0.add(gdstk.Reference(nmos_4t_95495835_x1_y1_1, (10.75,22.68), x_reflection=True))
opamp_adc_0.add(gdstk.Label('VDD', (8.17,3.57), layer=69, texttype=5))
opamp_adc_0.add(gdstk.Label('VSS', (4.73,14.28), layer=68, texttype=5))
opamp_adc_0.add(gdstk.Label('DOUT', (2.58,22.26), layer=68, texttype=5))
opamp_adc_0.add(gdstk.Label('VOUT', (1.72,13.86), layer=70, texttype=5))
opamp_adc_0.add(gdstk.Label('VBIAS', (6.45,18.06), layer=68, texttype=5))
opamp_adc_0.add(gdstk.Label('VINN', (4.73,12.18), layer=68, texttype=5))
opamp_adc_0.add(gdstk.Label('VINP', (6.45,12.18), layer=68, texttype=5))
opamp_adc_0.add(gdstk.Label('VREF', (11.61,18.06), layer=68, texttype=5))

lib.write_gds('OPAMP_ADC_0.gds')
